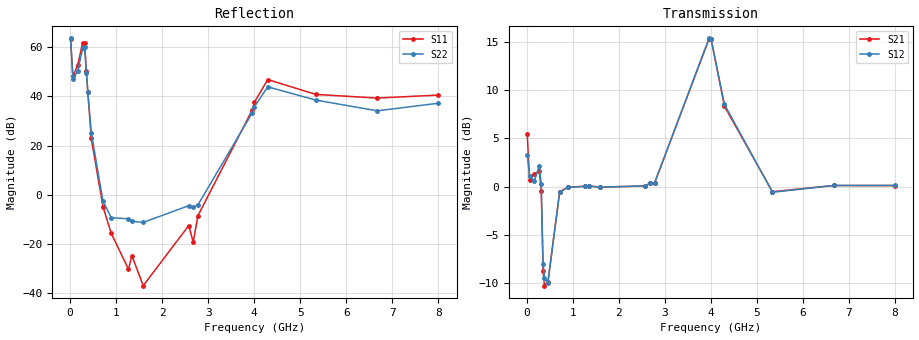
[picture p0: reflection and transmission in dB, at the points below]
!Agilent Technologies,N5230A,US43500312,A.07.50.67
!Agilent N5230A: A.07.50.67
!Date: Tuesday, June 09, 2015 15:37:26
!Correction: S11(Full 2 Port(1,2))
!S21(Full 2 Port(1,2))
!S12(Full 2 Port(1,2))
!S22(Full 2 Port(1,2))
!S2P File: Measurements: S11, S21, S12, S22:
# Hz S  MA  R 50
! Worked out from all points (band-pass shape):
!   1601 points, 10 MHz to 8 GHz, reference 50 ohm
!   highest |S21| = 15.32 dB at 3.96 GHz (marker M1); lowest = -10.3 dB at 384.5 MHz (marker M2)
!   |S21| within 3 dB of the highest: 3.765 GHz to 4.203 GHz (438.2 MHz wide, 11 % of centre)
!   lowest |S11| = -37.0 dB at 1.588 GHz (marker M3), VSWR 1.03, Z = 49.2 - j1.17 ohm
!   |S11| at or under -10 dB: 834.4 MHz to 2.109 GHz (1.275 GHz wide, 86.6 % of centre); 2.532 GHz to 2.757 GHz (224.9 MHz wide, 8.51 % of centre); 3.271 GHz to 3.349 GHz (78.34 MHz wide, 2.37 % of centre)
!   |S22| runs from -13.6 to 63.6 dB; largest |S21 - S12| = 0.73
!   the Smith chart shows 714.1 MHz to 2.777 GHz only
!   S11 on the Smith chart (normalised r, x): 714.1 MHz: 0.27, -0.02; 893.9 MHz: 0.87, -0.28; 1.268 GHz: 1.06, +0.03; 2.577 GHz: 0.66, -0.19; 2.777 GHz: 2.20, -0.02
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1e7  1495 171.1  1.875 1.8  1.463 -18.9  1520 -19.5
5.99375e7  256 327.3  1.08 1.1  1.14 3.7  229.7 92.6
1.648062e8  429.5 405.1  1.159 8.6  1.069 4.4  324.7 126.4
2.69675e8  1219 391.3  1.209 -6.0  1.276 -11.2  946.6 107.3
3.146188e8  1216 430.6  0.9529 42.9  1.028 48.7  1010 151.7
3.545688e8  323.3 451.4  0.3653 34.2  0.3944 37.0  294.8 181.5
3.845312e8  123.1 449.3  0.306 29.0  0.3349 27.8  122.8 189.0
4.594375e8  14.08 442.0  0.3217 33.5  0.3163 33.8  18.32 219.3
7.141188e8  0.5746 541.9  0.9397 57.5  0.9333 57.4  0.7404 441.4
8.938938e8  0.1641 613.8  0.9923 51.4  0.9893 51.3  0.3414 531.3
1.268425e9  0.03052 747.0  1.004 52.4  1.004 52.5  0.324 720.8
1.343331e9  0.05778 870.1  1.008 52.6  1.007 52.7  0.2905 761.8
1.588025e9  0.01413 957.4  0.9932 52.0  0.9936 52.1  0.2735 860.8
2.576788e9  0.2351 934.6  1.007 55.0  1.009 55.0  0.5999 1184.5
2.676662e9  0.1093 1030.9  1.04 55.4  1.043 55.4  0.5532 1218.5
2.776538e9  0.3745 1079.5  1.041 55.2  1.044 55.2  0.6211 1257.1
3.960056e9  53.64 1065.9  5.833 40.8  5.876 40.9  46.76 1532.8
4.005e9  76.54 1061.6  5.823 29.0  5.83 29.1  62.1 1527.6
4.294638e9  220.6 994.5  2.611 -44.8  2.671 -44.3  156.8 1456.0
5.338331e9  110.1 972.7  0.9407 8.4  0.9342 8.4  84.44 1406.1
6.671662e9  92.76 1005.8  1.013 7.6  1.013 7.6  51.06 1345.7
8e9  106.7 1030.8  1.012 5.3  1.014 5.2  72.71 1311.5
